One B-rep face of a CAD part: STEP entity #540.
In plain terms, the planar face has unit normal (1, 0, 0).
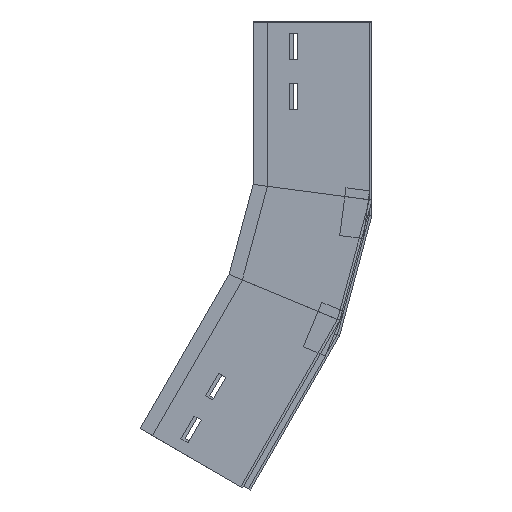
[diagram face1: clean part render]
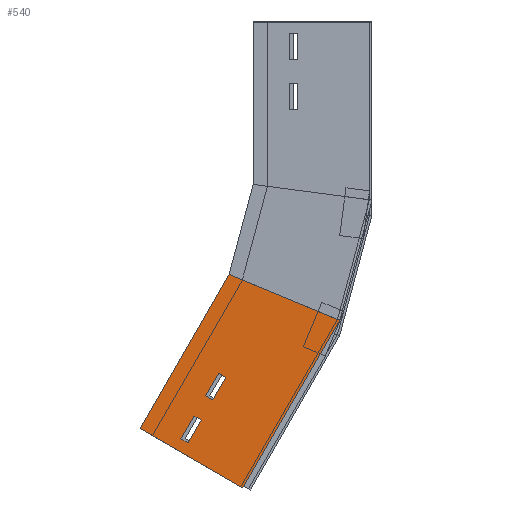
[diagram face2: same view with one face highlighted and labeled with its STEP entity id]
Its self-contained STEP definition (entity closure, numbers rounded to 3 decimals):
#11 = VERTEX_POINT ( 'NONE', #1213 ) ;
#21 = VERTEX_POINT ( 'NONE', #67 ) ;
#63 = VECTOR ( 'NONE', #1111, 1000. ) ;
#67 = CARTESIAN_POINT ( 'NONE',  ( 0., 66., -73.505 ) ) ;
#72 = EDGE_CURVE ( 'NONE', #11, #656, #75, .T. ) ;
#75 = LINE ( 'NONE', #542, #1269 ) ;
#95 = DIRECTION ( 'NONE',  ( 0., 0., -1. ) ) ;
#111 = CARTESIAN_POINT ( 'NONE',  ( 0., 66., -51.505 ) ) ;
#120 = FACE_BOUND ( 'NONE', #1174, .T. ) ;
#128 = EDGE_CURVE ( 'NONE', #417, #11, #930, .T. ) ;
#146 = CARTESIAN_POINT ( 'NONE',  ( 0., 59., -9.835 ) ) ;
#158 = DIRECTION ( 'NONE',  ( 0., 0., 1. ) ) ;
#159 = VERTEX_POINT ( 'NONE', #545 ) ;
#168 = ORIENTED_EDGE ( 'NONE', *, *, #758, .T. ) ;
#177 = EDGE_LOOP ( 'NONE', ( #309, #1068, #1027, #674 ) ) ;
#195 = LINE ( 'NONE', #421, #63 ) ;
#211 = CARTESIAN_POINT ( 'NONE',  ( 0., 66., -9.835 ) ) ;
#236 = EDGE_CURVE ( 'NONE', #648, #615, #302, .T. ) ;
#279 = ORIENTED_EDGE ( 'NONE', *, *, #915, .T. ) ;
#286 = CARTESIAN_POINT ( 'NONE',  ( 0., 100., 0. ) ) ;
#302 = LINE ( 'NONE', #637, #1418 ) ;
#309 = ORIENTED_EDGE ( 'NONE', *, *, #466, .T. ) ;
#324 = EDGE_CURVE ( 'NONE', #921, #159, #195, .T. ) ;
#331 = CARTESIAN_POINT ( 'NONE',  ( 0., 59., -73.505 ) ) ;
#339 = VECTOR ( 'NONE', #593, 1000. ) ;
#368 = CARTESIAN_POINT ( 'NONE',  ( 0., 59., -31.835 ) ) ;
#374 = EDGE_CURVE ( 'NONE', #726, #21, #1117, .T. ) ;
#377 = CARTESIAN_POINT ( 'NONE',  ( 0., 66., -31.835 ) ) ;
#403 = VECTOR ( 'NONE', #694, 1000. ) ;
#413 = CARTESIAN_POINT ( 'NONE',  ( 0., 0., 0. ) ) ;
#417 = VERTEX_POINT ( 'NONE', #146 ) ;
#421 = CARTESIAN_POINT ( 'NONE',  ( 0., 21.094, -160.223 ) ) ;
#440 = ORIENTED_EDGE ( 'NONE', *, *, #613, .F. ) ;
#466 = EDGE_CURVE ( 'NONE', #615, #726, #862, .T. ) ;
#473 = EDGE_CURVE ( 'NONE', #1051, #921, #870, .T. ) ;
#477 = CARTESIAN_POINT ( 'NONE',  ( 0., 0., 0. ) ) ;
#491 = VECTOR ( 'NONE', #986, 1000. ) ;
#501 = CARTESIAN_POINT ( 'NONE',  ( 0., 59., -9.835 ) ) ;
#540 = ADVANCED_FACE ( 'NONE', ( #1034, #1253, #120 ), #1058, .F. ) ;
#542 = CARTESIAN_POINT ( 'NONE',  ( 0., 66., -9.835 ) ) ;
#545 = CARTESIAN_POINT ( 'NONE',  ( 0., 0., -163. ) ) ;
#593 = DIRECTION ( 'NONE',  ( 0., 1., 0. ) ) ;
#604 = DIRECTION ( 'NONE',  ( 0., -1., 0. ) ) ;
#613 = EDGE_CURVE ( 'NONE', #962, #1051, #718, .T. ) ;
#615 = VERTEX_POINT ( 'NONE', #1070 ) ;
#637 = CARTESIAN_POINT ( 'NONE',  ( 0., 59., -51.505 ) ) ;
#641 = CARTESIAN_POINT ( 'NONE',  ( 0., 66., -73.505 ) ) ;
#647 = AXIS2_PLACEMENT_3D ( 'NONE', #477, #1342, #1350 ) ;
#648 = VERTEX_POINT ( 'NONE', #331 ) ;
#656 = VERTEX_POINT ( 'NONE', #1459 ) ;
#657 = VECTOR ( 'NONE', #604, 1000. ) ;
#674 = ORIENTED_EDGE ( 'NONE', *, *, #236, .T. ) ;
#693 = DIRECTION ( 'NONE',  ( 0., 1., 0. ) ) ;
#694 = DIRECTION ( 'NONE',  ( 0., 1., 0. ) ) ;
#696 = CARTESIAN_POINT ( 'NONE',  ( 0., 100., -149.835 ) ) ;
#698 = CARTESIAN_POINT ( 'NONE',  ( 0., 66., -51.505 ) ) ;
#718 = LINE ( 'NONE', #1177, #403 ) ;
#724 = ORIENTED_EDGE ( 'NONE', *, *, #128, .T. ) ;
#726 = VERTEX_POINT ( 'NONE', #734 ) ;
#734 = CARTESIAN_POINT ( 'NONE',  ( 0., 66., -51.505 ) ) ;
#744 = VECTOR ( 'NONE', #95, 1000. ) ;
#754 = DIRECTION ( 'NONE',  ( 0., 0., 1. ) ) ;
#758 = EDGE_CURVE ( 'NONE', #656, #1211, #1365, .T. ) ;
#816 = ORIENTED_EDGE ( 'NONE', *, *, #324, .F. ) ;
#822 = LINE ( 'NONE', #1283, #1149 ) ;
#862 = LINE ( 'NONE', #698, #339 ) ;
#870 = LINE ( 'NONE', #286, #1172 ) ;
#876 = VECTOR ( 'NONE', #693, 1000. ) ;
#915 = EDGE_CURVE ( 'NONE', #1211, #417, #1065, .T. ) ;
#916 = VECTOR ( 'NONE', #158, 1000. ) ;
#921 = VERTEX_POINT ( 'NONE', #696 ) ;
#930 = LINE ( 'NONE', #211, #876 ) ;
#937 = DIRECTION ( 'NONE',  ( 0., 0., -1. ) ) ;
#962 = VERTEX_POINT ( 'NONE', #413 ) ;
#986 = DIRECTION ( 'NONE',  ( 0., -1., 0. ) ) ;
#997 = EDGE_CURVE ( 'NONE', #21, #648, #1210, .T. ) ;
#1022 = ORIENTED_EDGE ( 'NONE', *, *, #473, .F. ) ;
#1027 = ORIENTED_EDGE ( 'NONE', *, *, #997, .T. ) ;
#1034 = FACE_BOUND ( 'NONE', #177, .T. ) ;
#1051 = VERTEX_POINT ( 'NONE', #1190 ) ;
#1058 = PLANE ( 'NONE',  #647 ) ;
#1065 = LINE ( 'NONE', #501, #916 ) ;
#1068 = ORIENTED_EDGE ( 'NONE', *, *, #374, .T. ) ;
#1070 = CARTESIAN_POINT ( 'NONE',  ( 0., 59., -51.505 ) ) ;
#1111 = DIRECTION ( 'NONE',  ( 0., -0.991, -0.131 ) ) ;
#1117 = LINE ( 'NONE', #111, #744 ) ;
#1149 = VECTOR ( 'NONE', #937, 1000. ) ;
#1154 = EDGE_CURVE ( 'NONE', #962, #159, #822, .T. ) ;
#1172 = VECTOR ( 'NONE', #1311, 1000. ) ;
#1174 = EDGE_LOOP ( 'NONE', ( #724, #1266, #168, #279 ) ) ;
#1177 = CARTESIAN_POINT ( 'NONE',  ( 0., 0., 0. ) ) ;
#1190 = CARTESIAN_POINT ( 'NONE',  ( 0., 100., 0. ) ) ;
#1210 = LINE ( 'NONE', #641, #491 ) ;
#1211 = VERTEX_POINT ( 'NONE', #368 ) ;
#1213 = CARTESIAN_POINT ( 'NONE',  ( 0., 66., -9.835 ) ) ;
#1222 = EDGE_LOOP ( 'NONE', ( #1022, #440, #1260, #816 ) ) ;
#1253 = FACE_OUTER_BOUND ( 'NONE', #1222, .T. ) ;
#1260 = ORIENTED_EDGE ( 'NONE', *, *, #1154, .T. ) ;
#1266 = ORIENTED_EDGE ( 'NONE', *, *, #72, .T. ) ;
#1269 = VECTOR ( 'NONE', #1455, 1000. ) ;
#1283 = CARTESIAN_POINT ( 'NONE',  ( 0., 0., 0. ) ) ;
#1311 = DIRECTION ( 'NONE',  ( 0., 0., -1. ) ) ;
#1342 = DIRECTION ( 'NONE',  ( -1., 0., 0. ) ) ;
#1350 = DIRECTION ( 'NONE',  ( 0., 0., 1. ) ) ;
#1365 = LINE ( 'NONE', #377, #657 ) ;
#1418 = VECTOR ( 'NONE', #754, 1000. ) ;
#1455 = DIRECTION ( 'NONE',  ( 0., 0., -1. ) ) ;
#1459 = CARTESIAN_POINT ( 'NONE',  ( 0., 66., -31.835 ) ) ;
